VERSION 5.7 ;
BUSBITCHARS "[]" ;
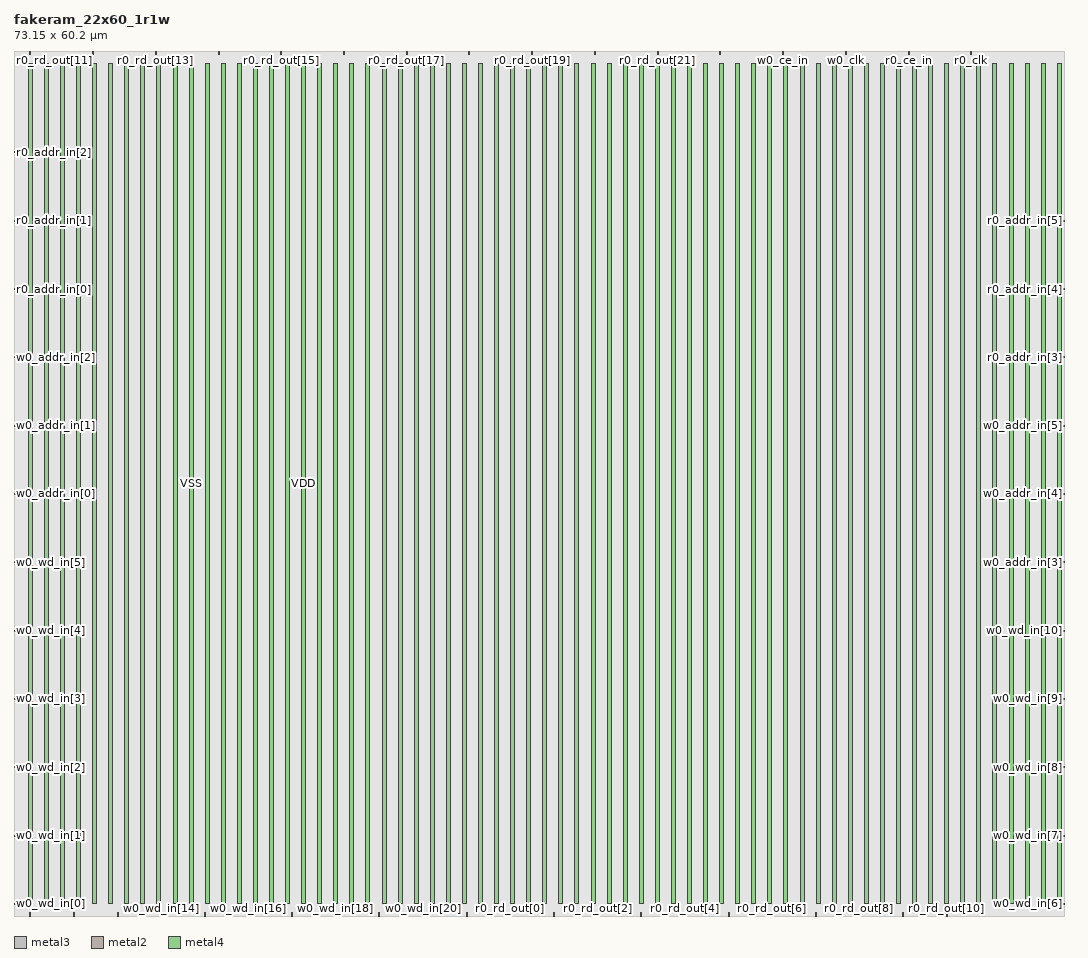
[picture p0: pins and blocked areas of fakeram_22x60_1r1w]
MACRO fakeram_22x60_1r1w
  FOREIGN fakeram_22x60_1r1w 0 0 ;
  SYMMETRY X Y R90 ;
  SIZE 73.150 BY 60.200 ;
  CLASS BLOCK ;
  PIN w0_wd_in[0]
    DIRECTION INPUT ;
    USE SIGNAL ;
    SHAPE ABUTMENT ;
    PORT
      LAYER metal3 ;
      RECT 0.000 0.805 0.210 0.875 ;
    END
  END w0_wd_in[0]
  PIN w0_wd_in[1]
    DIRECTION INPUT ;
    USE SIGNAL ;
    SHAPE ABUTMENT ;
    PORT
      LAYER metal3 ;
      RECT 0.000 5.565 0.210 5.635 ;
    END
  END w0_wd_in[1]
  PIN w0_wd_in[2]
    DIRECTION INPUT ;
    USE SIGNAL ;
    SHAPE ABUTMENT ;
    PORT
      LAYER metal3 ;
      RECT 0.000 10.325 0.210 10.395 ;
    END
  END w0_wd_in[2]
  PIN w0_wd_in[3]
    DIRECTION INPUT ;
    USE SIGNAL ;
    SHAPE ABUTMENT ;
    PORT
      LAYER metal3 ;
      RECT 0.000 15.085 0.210 15.155 ;
    END
  END w0_wd_in[3]
  PIN w0_wd_in[4]
    DIRECTION INPUT ;
    USE SIGNAL ;
    SHAPE ABUTMENT ;
    PORT
      LAYER metal3 ;
      RECT 0.000 19.845 0.210 19.915 ;
    END
  END w0_wd_in[4]
  PIN w0_wd_in[5]
    DIRECTION INPUT ;
    USE SIGNAL ;
    SHAPE ABUTMENT ;
    PORT
      LAYER metal3 ;
      RECT 0.000 24.605 0.210 24.675 ;
    END
  END w0_wd_in[5]
  PIN w0_wd_in[6]
    DIRECTION INPUT ;
    USE SIGNAL ;
    SHAPE ABUTMENT ;
    PORT
      LAYER metal3 ;
      RECT 72.940 0.805 73.150 0.875 ;
    END
  END w0_wd_in[6]
  PIN w0_wd_in[7]
    DIRECTION INPUT ;
    USE SIGNAL ;
    SHAPE ABUTMENT ;
    PORT
      LAYER metal3 ;
      RECT 72.940 5.565 73.150 5.635 ;
    END
  END w0_wd_in[7]
  PIN w0_wd_in[8]
    DIRECTION INPUT ;
    USE SIGNAL ;
    SHAPE ABUTMENT ;
    PORT
      LAYER metal3 ;
      RECT 72.940 10.325 73.150 10.395 ;
    END
  END w0_wd_in[8]
  PIN w0_wd_in[9]
    DIRECTION INPUT ;
    USE SIGNAL ;
    SHAPE ABUTMENT ;
    PORT
      LAYER metal3 ;
      RECT 72.940 15.085 73.150 15.155 ;
    END
  END w0_wd_in[9]
  PIN w0_wd_in[10]
    DIRECTION INPUT ;
    USE SIGNAL ;
    SHAPE ABUTMENT ;
    PORT
      LAYER metal3 ;
      RECT 72.940 19.845 73.150 19.915 ;
    END
  END w0_wd_in[10]
  PIN w0_wd_in[11]
    DIRECTION INPUT ;
    USE SIGNAL ;
    SHAPE ABUTMENT ;
    PORT
      LAYER metal2 ;
      RECT 1.105 0.000 1.175 0.210 ;
    END
  END w0_wd_in[11]
  PIN w0_wd_in[12]
    DIRECTION INPUT ;
    USE SIGNAL ;
    SHAPE ABUTMENT ;
    PORT
      LAYER metal2 ;
      RECT 4.145 0.000 4.215 0.210 ;
    END
  END w0_wd_in[12]
  PIN w0_wd_in[13]
    DIRECTION INPUT ;
    USE SIGNAL ;
    SHAPE ABUTMENT ;
    PORT
      LAYER metal2 ;
      RECT 7.185 0.000 7.255 0.210 ;
    END
  END w0_wd_in[13]
  PIN w0_wd_in[14]
    DIRECTION INPUT ;
    USE SIGNAL ;
    SHAPE ABUTMENT ;
    PORT
      LAYER metal2 ;
      RECT 10.225 0.000 10.295 0.210 ;
    END
  END w0_wd_in[14]
  PIN w0_wd_in[15]
    DIRECTION INPUT ;
    USE SIGNAL ;
    SHAPE ABUTMENT ;
    PORT
      LAYER metal2 ;
      RECT 13.265 0.000 13.335 0.210 ;
    END
  END w0_wd_in[15]
  PIN w0_wd_in[16]
    DIRECTION INPUT ;
    USE SIGNAL ;
    SHAPE ABUTMENT ;
    PORT
      LAYER metal2 ;
      RECT 16.305 0.000 16.375 0.210 ;
    END
  END w0_wd_in[16]
  PIN w0_wd_in[17]
    DIRECTION INPUT ;
    USE SIGNAL ;
    SHAPE ABUTMENT ;
    PORT
      LAYER metal2 ;
      RECT 19.345 0.000 19.415 0.210 ;
    END
  END w0_wd_in[17]
  PIN w0_wd_in[18]
    DIRECTION INPUT ;
    USE SIGNAL ;
    SHAPE ABUTMENT ;
    PORT
      LAYER metal2 ;
      RECT 22.385 0.000 22.455 0.210 ;
    END
  END w0_wd_in[18]
  PIN w0_wd_in[19]
    DIRECTION INPUT ;
    USE SIGNAL ;
    SHAPE ABUTMENT ;
    PORT
      LAYER metal2 ;
      RECT 25.425 0.000 25.495 0.210 ;
    END
  END w0_wd_in[19]
  PIN w0_wd_in[20]
    DIRECTION INPUT ;
    USE SIGNAL ;
    SHAPE ABUTMENT ;
    PORT
      LAYER metal2 ;
      RECT 28.465 0.000 28.535 0.210 ;
    END
  END w0_wd_in[20]
  PIN w0_wd_in[21]
    DIRECTION INPUT ;
    USE SIGNAL ;
    SHAPE ABUTMENT ;
    PORT
      LAYER metal2 ;
      RECT 31.505 0.000 31.575 0.210 ;
    END
  END w0_wd_in[21]
  PIN r0_rd_out[0]
    DIRECTION OUTPUT ;
    USE SIGNAL ;
    SHAPE ABUTMENT ;
    PORT
      LAYER metal2 ;
      RECT 34.545 0.000 34.615 0.210 ;
    END
  END r0_rd_out[0]
  PIN r0_rd_out[1]
    DIRECTION OUTPUT ;
    USE SIGNAL ;
    SHAPE ABUTMENT ;
    PORT
      LAYER metal2 ;
      RECT 37.585 0.000 37.655 0.210 ;
    END
  END r0_rd_out[1]
  PIN r0_rd_out[2]
    DIRECTION OUTPUT ;
    USE SIGNAL ;
    SHAPE ABUTMENT ;
    PORT
      LAYER metal2 ;
      RECT 40.625 0.000 40.695 0.210 ;
    END
  END r0_rd_out[2]
  PIN r0_rd_out[3]
    DIRECTION OUTPUT ;
    USE SIGNAL ;
    SHAPE ABUTMENT ;
    PORT
      LAYER metal2 ;
      RECT 43.665 0.000 43.735 0.210 ;
    END
  END r0_rd_out[3]
  PIN r0_rd_out[4]
    DIRECTION OUTPUT ;
    USE SIGNAL ;
    SHAPE ABUTMENT ;
    PORT
      LAYER metal2 ;
      RECT 46.705 0.000 46.775 0.210 ;
    END
  END r0_rd_out[4]
  PIN r0_rd_out[5]
    DIRECTION OUTPUT ;
    USE SIGNAL ;
    SHAPE ABUTMENT ;
    PORT
      LAYER metal2 ;
      RECT 49.745 0.000 49.815 0.210 ;
    END
  END r0_rd_out[5]
  PIN r0_rd_out[6]
    DIRECTION OUTPUT ;
    USE SIGNAL ;
    SHAPE ABUTMENT ;
    PORT
      LAYER metal2 ;
      RECT 52.785 0.000 52.855 0.210 ;
    END
  END r0_rd_out[6]
  PIN r0_rd_out[7]
    DIRECTION OUTPUT ;
    USE SIGNAL ;
    SHAPE ABUTMENT ;
    PORT
      LAYER metal2 ;
      RECT 55.825 0.000 55.895 0.210 ;
    END
  END r0_rd_out[7]
  PIN r0_rd_out[8]
    DIRECTION OUTPUT ;
    USE SIGNAL ;
    SHAPE ABUTMENT ;
    PORT
      LAYER metal2 ;
      RECT 58.865 0.000 58.935 0.210 ;
    END
  END r0_rd_out[8]
  PIN r0_rd_out[9]
    DIRECTION OUTPUT ;
    USE SIGNAL ;
    SHAPE ABUTMENT ;
    PORT
      LAYER metal2 ;
      RECT 61.905 0.000 61.975 0.210 ;
    END
  END r0_rd_out[9]
  PIN r0_rd_out[10]
    DIRECTION OUTPUT ;
    USE SIGNAL ;
    SHAPE ABUTMENT ;
    PORT
      LAYER metal2 ;
      RECT 64.945 0.000 65.015 0.210 ;
    END
  END r0_rd_out[10]
  PIN r0_rd_out[11]
    DIRECTION OUTPUT ;
    USE SIGNAL ;
    SHAPE ABUTMENT ;
    PORT
      LAYER metal2 ;
      RECT 1.105 59.990 1.175 60.200 ;
    END
  END r0_rd_out[11]
  PIN r0_rd_out[12]
    DIRECTION OUTPUT ;
    USE SIGNAL ;
    SHAPE ABUTMENT ;
    PORT
      LAYER metal2 ;
      RECT 5.475 59.990 5.545 60.200 ;
    END
  END r0_rd_out[12]
  PIN r0_rd_out[13]
    DIRECTION OUTPUT ;
    USE SIGNAL ;
    SHAPE ABUTMENT ;
    PORT
      LAYER metal2 ;
      RECT 9.845 59.990 9.915 60.200 ;
    END
  END r0_rd_out[13]
  PIN r0_rd_out[14]
    DIRECTION OUTPUT ;
    USE SIGNAL ;
    SHAPE ABUTMENT ;
    PORT
      LAYER metal2 ;
      RECT 14.215 59.990 14.285 60.200 ;
    END
  END r0_rd_out[14]
  PIN r0_rd_out[15]
    DIRECTION OUTPUT ;
    USE SIGNAL ;
    SHAPE ABUTMENT ;
    PORT
      LAYER metal2 ;
      RECT 18.585 59.990 18.655 60.200 ;
    END
  END r0_rd_out[15]
  PIN r0_rd_out[16]
    DIRECTION OUTPUT ;
    USE SIGNAL ;
    SHAPE ABUTMENT ;
    PORT
      LAYER metal2 ;
      RECT 22.955 59.990 23.025 60.200 ;
    END
  END r0_rd_out[16]
  PIN r0_rd_out[17]
    DIRECTION OUTPUT ;
    USE SIGNAL ;
    SHAPE ABUTMENT ;
    PORT
      LAYER metal2 ;
      RECT 27.325 59.990 27.395 60.200 ;
    END
  END r0_rd_out[17]
  PIN r0_rd_out[18]
    DIRECTION OUTPUT ;
    USE SIGNAL ;
    SHAPE ABUTMENT ;
    PORT
      LAYER metal2 ;
      RECT 31.695 59.990 31.765 60.200 ;
    END
  END r0_rd_out[18]
  PIN r0_rd_out[19]
    DIRECTION OUTPUT ;
    USE SIGNAL ;
    SHAPE ABUTMENT ;
    PORT
      LAYER metal2 ;
      RECT 36.065 59.990 36.135 60.200 ;
    END
  END r0_rd_out[19]
  PIN r0_rd_out[20]
    DIRECTION OUTPUT ;
    USE SIGNAL ;
    SHAPE ABUTMENT ;
    PORT
      LAYER metal2 ;
      RECT 40.435 59.990 40.505 60.200 ;
    END
  END r0_rd_out[20]
  PIN r0_rd_out[21]
    DIRECTION OUTPUT ;
    USE SIGNAL ;
    SHAPE ABUTMENT ;
    PORT
      LAYER metal2 ;
      RECT 44.805 59.990 44.875 60.200 ;
    END
  END r0_rd_out[21]
  PIN w0_addr_in[0]
    DIRECTION INPUT ;
    USE SIGNAL ;
    SHAPE ABUTMENT ;
    PORT
      LAYER metal3 ;
      RECT 0.000 29.365 0.210 29.435 ;
    END
  END w0_addr_in[0]
  PIN w0_addr_in[1]
    DIRECTION INPUT ;
    USE SIGNAL ;
    SHAPE ABUTMENT ;
    PORT
      LAYER metal3 ;
      RECT 0.000 34.125 0.210 34.195 ;
    END
  END w0_addr_in[1]
  PIN w0_addr_in[2]
    DIRECTION INPUT ;
    USE SIGNAL ;
    SHAPE ABUTMENT ;
    PORT
      LAYER metal3 ;
      RECT 0.000 38.885 0.210 38.955 ;
    END
  END w0_addr_in[2]
  PIN w0_addr_in[3]
    DIRECTION INPUT ;
    USE SIGNAL ;
    SHAPE ABUTMENT ;
    PORT
      LAYER metal3 ;
      RECT 72.940 24.605 73.150 24.675 ;
    END
  END w0_addr_in[3]
  PIN w0_addr_in[4]
    DIRECTION INPUT ;
    USE SIGNAL ;
    SHAPE ABUTMENT ;
    PORT
      LAYER metal3 ;
      RECT 72.940 29.365 73.150 29.435 ;
    END
  END w0_addr_in[4]
  PIN w0_addr_in[5]
    DIRECTION INPUT ;
    USE SIGNAL ;
    SHAPE ABUTMENT ;
    PORT
      LAYER metal3 ;
      RECT 72.940 34.125 73.150 34.195 ;
    END
  END w0_addr_in[5]
  PIN r0_addr_in[0]
    DIRECTION INPUT ;
    USE SIGNAL ;
    SHAPE ABUTMENT ;
    PORT
      LAYER metal3 ;
      RECT 0.000 43.645 0.210 43.715 ;
    END
  END r0_addr_in[0]
  PIN r0_addr_in[1]
    DIRECTION INPUT ;
    USE SIGNAL ;
    SHAPE ABUTMENT ;
    PORT
      LAYER metal3 ;
      RECT 0.000 48.405 0.210 48.475 ;
    END
  END r0_addr_in[1]
  PIN r0_addr_in[2]
    DIRECTION INPUT ;
    USE SIGNAL ;
    SHAPE ABUTMENT ;
    PORT
      LAYER metal3 ;
      RECT 0.000 53.165 0.210 53.235 ;
    END
  END r0_addr_in[2]
  PIN r0_addr_in[3]
    DIRECTION INPUT ;
    USE SIGNAL ;
    SHAPE ABUTMENT ;
    PORT
      LAYER metal3 ;
      RECT 72.940 38.885 73.150 38.955 ;
    END
  END r0_addr_in[3]
  PIN r0_addr_in[4]
    DIRECTION INPUT ;
    USE SIGNAL ;
    SHAPE ABUTMENT ;
    PORT
      LAYER metal3 ;
      RECT 72.940 43.645 73.150 43.715 ;
    END
  END r0_addr_in[4]
  PIN r0_addr_in[5]
    DIRECTION INPUT ;
    USE SIGNAL ;
    SHAPE ABUTMENT ;
    PORT
      LAYER metal3 ;
      RECT 72.940 48.405 73.150 48.475 ;
    END
  END r0_addr_in[5]
  PIN w0_we_in
    DIRECTION INPUT ;
    USE SIGNAL ;
    SHAPE ABUTMENT ;
    PORT
      LAYER metal2 ;
      RECT 49.175 59.990 49.245 60.200 ;
    END
  END w0_we_in
  PIN w0_ce_in
    DIRECTION INPUT ;
    USE SIGNAL ;
    SHAPE ABUTMENT ;
    PORT
      LAYER metal2 ;
      RECT 53.545 59.990 53.615 60.200 ;
    END
  END w0_ce_in
  PIN w0_clk
    DIRECTION INPUT ;
    USE SIGNAL ;
    SHAPE ABUTMENT ;
    PORT
      LAYER metal2 ;
      RECT 57.915 59.990 57.985 60.200 ;
    END
  END w0_clk
  PIN r0_ce_in
    DIRECTION INPUT ;
    USE SIGNAL ;
    SHAPE ABUTMENT ;
    PORT
      LAYER metal2 ;
      RECT 62.285 59.990 62.355 60.200 ;
    END
  END r0_ce_in
  PIN r0_clk
    DIRECTION INPUT ;
    USE SIGNAL ;
    SHAPE ABUTMENT ;
    PORT
      LAYER metal2 ;
      RECT 66.655 59.990 66.725 60.200 ;
    END
  END r0_clk
  PIN VSS
    DIRECTION INOUT ;
    USE GROUND ;
    PORT
      LAYER metal4 ;
      RECT 1.000 0.840 1.280 59.360 ;
      RECT 3.240 0.840 3.520 59.360 ;
      RECT 5.480 0.840 5.760 59.360 ;
      RECT 7.720 0.840 8.000 59.360 ;
      RECT 9.960 0.840 10.240 59.360 ;
      RECT 12.200 0.840 12.480 59.360 ;
      RECT 14.440 0.840 14.720 59.360 ;
      RECT 16.680 0.840 16.960 59.360 ;
      RECT 18.920 0.840 19.200 59.360 ;
      RECT 21.160 0.840 21.440 59.360 ;
      RECT 23.400 0.840 23.680 59.360 ;
      RECT 25.640 0.840 25.920 59.360 ;
      RECT 27.880 0.840 28.160 59.360 ;
      RECT 30.120 0.840 30.400 59.360 ;
      RECT 32.360 0.840 32.640 59.360 ;
      RECT 34.600 0.840 34.880 59.360 ;
      RECT 36.840 0.840 37.120 59.360 ;
      RECT 39.080 0.840 39.360 59.360 ;
      RECT 41.320 0.840 41.600 59.360 ;
      RECT 43.560 0.840 43.840 59.360 ;
      RECT 45.800 0.840 46.080 59.360 ;
      RECT 48.040 0.840 48.320 59.360 ;
      RECT 50.280 0.840 50.560 59.360 ;
      RECT 52.520 0.840 52.800 59.360 ;
      RECT 54.760 0.840 55.040 59.360 ;
      RECT 57.000 0.840 57.280 59.360 ;
      RECT 59.240 0.840 59.520 59.360 ;
      RECT 61.480 0.840 61.760 59.360 ;
      RECT 63.720 0.840 64.000 59.360 ;
      RECT 65.960 0.840 66.240 59.360 ;
      RECT 68.200 0.840 68.480 59.360 ;
      RECT 70.440 0.840 70.720 59.360 ;
      RECT 72.680 0.840 72.960 59.360 ;
    END
  END VSS
  PIN VDD
    DIRECTION INOUT ;
    USE POWER ;
    PORT
      LAYER metal4 ;
      RECT 2.120 0.840 2.400 59.360 ;
      RECT 4.360 0.840 4.640 59.360 ;
      RECT 6.600 0.840 6.880 59.360 ;
      RECT 8.840 0.840 9.120 59.360 ;
      RECT 11.080 0.840 11.360 59.360 ;
      RECT 13.320 0.840 13.600 59.360 ;
      RECT 15.560 0.840 15.840 59.360 ;
      RECT 17.800 0.840 18.080 59.360 ;
      RECT 20.040 0.840 20.320 59.360 ;
      RECT 22.280 0.840 22.560 59.360 ;
      RECT 24.520 0.840 24.800 59.360 ;
      RECT 26.760 0.840 27.040 59.360 ;
      RECT 29.000 0.840 29.280 59.360 ;
      RECT 31.240 0.840 31.520 59.360 ;
      RECT 33.480 0.840 33.760 59.360 ;
      RECT 35.720 0.840 36.000 59.360 ;
      RECT 37.960 0.840 38.240 59.360 ;
      RECT 40.200 0.840 40.480 59.360 ;
      RECT 42.440 0.840 42.720 59.360 ;
      RECT 44.680 0.840 44.960 59.360 ;
      RECT 46.920 0.840 47.200 59.360 ;
      RECT 49.160 0.840 49.440 59.360 ;
      RECT 51.400 0.840 51.680 59.360 ;
      RECT 53.640 0.840 53.920 59.360 ;
      RECT 55.880 0.840 56.160 59.360 ;
      RECT 58.120 0.840 58.400 59.360 ;
      RECT 60.360 0.840 60.640 59.360 ;
      RECT 62.600 0.840 62.880 59.360 ;
      RECT 64.840 0.840 65.120 59.360 ;
      RECT 67.080 0.840 67.360 59.360 ;
      RECT 69.320 0.840 69.600 59.360 ;
      RECT 71.560 0.840 71.840 59.360 ;
    END
  END VDD
  OBS
    LAYER metal1 ;
    RECT 0 0 73.150 60.200 ;
    LAYER metal2 ;
    RECT 0 0 73.150 60.200 ;
    LAYER metal3 ;
    RECT 0 0 73.150 60.200 ;
    LAYER metal4 ;
    RECT 0 0 73.150 60.200 ;
    LAYER OVERLAP ;
    RECT 0 0 73.150 60.200 ;
  END
END fakeram_22x60_1r1w

END LIBRARY
